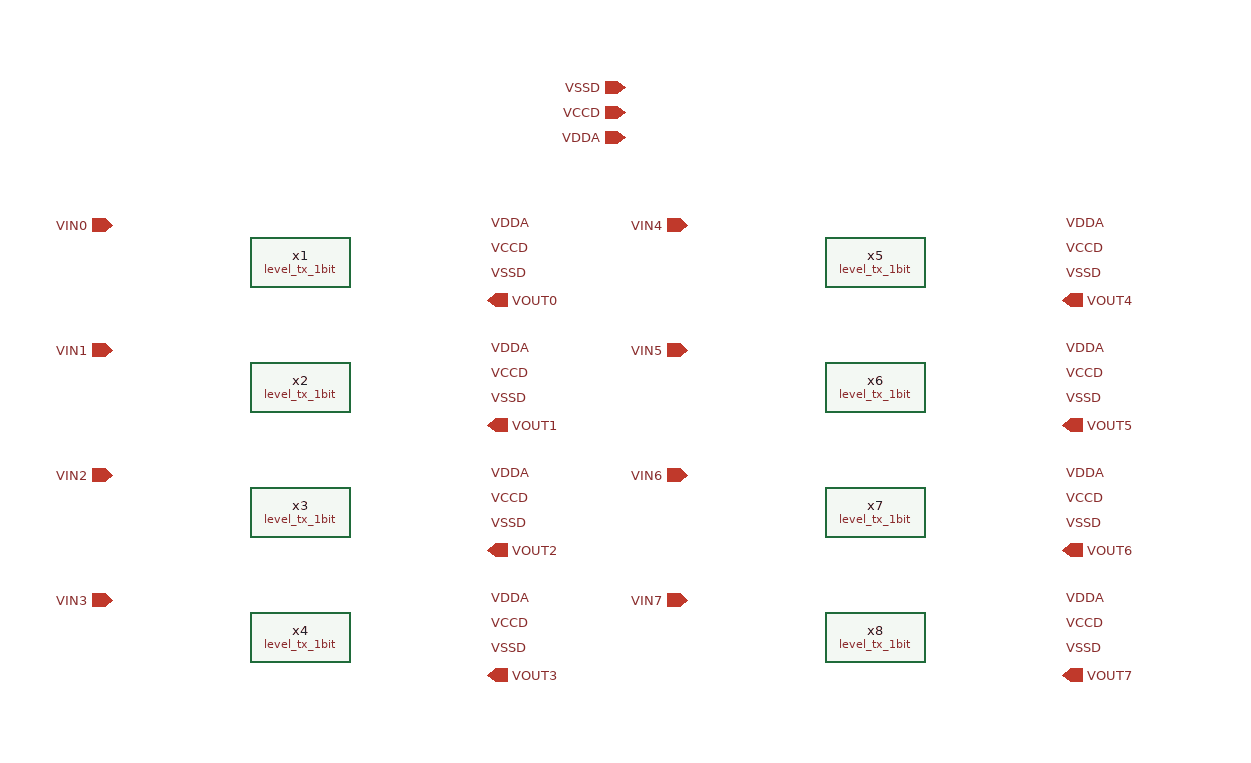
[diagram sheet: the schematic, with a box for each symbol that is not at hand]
v {xschem version=3.4.0 file_version=1.2
}
G {}
K {}
V {}
S {}
E {}
C {devices/iopin.sym} 390 -60 0 0 {name=p1 lab=VDDA}
C {devices/iopin.sym} 390 -80 0 0 {name=p5 lab=VCCD}
C {devices/iopin.sym} 390 -100 0 0 {name=p6 lab=VSSD}
C {devices/ipin.sym} -20 10 0 0 {name=p2 lab=VIN0}
C {devices/opin.sym} 280 70 0 0 {name=p3 lab=VOUT0}
C {devices/lab_pin.sym} 280 50 0 1 {name=p4 sig_type=std_logic lab=VSSD}
C {devices/lab_pin.sym} 280 10 0 1 {name=p7 sig_type=std_logic lab=VDDA}
C {devices/lab_pin.sym} 280 30 0 1 {name=p8 sig_type=std_logic lab=VCCD}
C {level_tx_1bit.sym} 130 40 0 0 {name=x1}
C {devices/ipin.sym} -20 110 0 0 {name=p9 lab=VIN1}
C {devices/opin.sym} 280 170 0 0 {name=p10 lab=VOUT1}
C {devices/lab_pin.sym} 280 150 0 1 {name=p11 sig_type=std_logic lab=VSSD}
C {devices/lab_pin.sym} 280 110 0 1 {name=p12 sig_type=std_logic lab=VDDA}
C {devices/lab_pin.sym} 280 130 0 1 {name=p13 sig_type=std_logic lab=VCCD}
C {level_tx_1bit.sym} 130 140 0 0 {name=x2}
C {devices/ipin.sym} -20 210 0 0 {name=p14 lab=VIN2}
C {devices/opin.sym} 280 270 0 0 {name=p15 lab=VOUT2}
C {devices/lab_pin.sym} 280 250 0 1 {name=p16 sig_type=std_logic lab=VSSD}
C {devices/lab_pin.sym} 280 210 0 1 {name=p17 sig_type=std_logic lab=VDDA}
C {devices/lab_pin.sym} 280 230 0 1 {name=p18 sig_type=std_logic lab=VCCD}
C {level_tx_1bit.sym} 130 240 0 0 {name=x3}
C {devices/ipin.sym} -20 310 0 0 {name=p19 lab=VIN3}
C {devices/opin.sym} 280 370 0 0 {name=p20 lab=VOUT3}
C {devices/lab_pin.sym} 280 350 0 1 {name=p21 sig_type=std_logic lab=VSSD}
C {devices/lab_pin.sym} 280 310 0 1 {name=p22 sig_type=std_logic lab=VDDA}
C {devices/lab_pin.sym} 280 330 0 1 {name=p23 sig_type=std_logic lab=VCCD}
C {level_tx_1bit.sym} 130 340 0 0 {name=x4}
C {devices/ipin.sym} 440 10 0 0 {name=p24 lab=VIN4}
C {devices/opin.sym} 740 70 0 0 {name=p25 lab=VOUT4}
C {devices/lab_pin.sym} 740 50 0 1 {name=p26 sig_type=std_logic lab=VSSD}
C {devices/lab_pin.sym} 740 10 0 1 {name=p27 sig_type=std_logic lab=VDDA}
C {devices/lab_pin.sym} 740 30 0 1 {name=p28 sig_type=std_logic lab=VCCD}
C {level_tx_1bit.sym} 590 40 0 0 {name=x5}
C {devices/ipin.sym} 440 110 0 0 {name=p29 lab=VIN5}
C {devices/opin.sym} 740 170 0 0 {name=p30 lab=VOUT5}
C {devices/lab_pin.sym} 740 150 0 1 {name=p31 sig_type=std_logic lab=VSSD}
C {devices/lab_pin.sym} 740 110 0 1 {name=p32 sig_type=std_logic lab=VDDA}
C {devices/lab_pin.sym} 740 130 0 1 {name=p33 sig_type=std_logic lab=VCCD}
C {level_tx_1bit.sym} 590 140 0 0 {name=x6}
C {devices/ipin.sym} 440 210 0 0 {name=p34 lab=VIN6}
C {devices/opin.sym} 740 270 0 0 {name=p35 lab=VOUT6}
C {devices/lab_pin.sym} 740 250 0 1 {name=p36 sig_type=std_logic lab=VSSD}
C {devices/lab_pin.sym} 740 210 0 1 {name=p37 sig_type=std_logic lab=VDDA}
C {devices/lab_pin.sym} 740 230 0 1 {name=p38 sig_type=std_logic lab=VCCD}
C {level_tx_1bit.sym} 590 240 0 0 {name=x7}
C {devices/ipin.sym} 440 310 0 0 {name=p39 lab=VIN7}
C {devices/opin.sym} 740 370 0 0 {name=p40 lab=VOUT7}
C {devices/lab_pin.sym} 740 350 0 1 {name=p41 sig_type=std_logic lab=VSSD}
C {devices/lab_pin.sym} 740 310 0 1 {name=p42 sig_type=std_logic lab=VDDA}
C {devices/lab_pin.sym} 740 330 0 1 {name=p43 sig_type=std_logic lab=VCCD}
C {level_tx_1bit.sym} 590 340 0 0 {name=x8}
